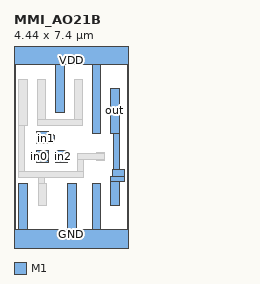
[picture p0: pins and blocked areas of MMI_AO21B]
MACRO MMI_AO21B
	CLASS CORE ;
	FOREIGN MMI_AO21B 0 0 ;
	SIZE 4.44 BY 7.4 ;
	SYMMETRY X Y ;
	SITE CORE1 ;
	PIN out
		DIRECTION output ;
		USE SIGNAL ;
		PORT
			LAYER M1 ;
			RECT 3.76 4.225 4.1 5.985 ;
			LAYER M1 ;
			RECT 3.87 2.815 4.1 4.225 ;
			LAYER M1 ;
			RECT 3.845 2.54 4.295 2.815 ;
			LAYER M1 ;
			RECT 3.76 2.365 4.295 2.54 ;
			LAYER M1 ;
			RECT 3.76 1.435 4.1 2.365 ;
		END
		AntennaDiffArea 1.3248 ;
	END out
	PIN in1
		DIRECTION input ;
		USE SIGNAL ;
		PORT
			LAYER M1 ;
			RECT 0.885 4.19 1.335 4.295 ;
			LAYER M1 ;
			RECT 0.885 4.135 1.52 4.19 ;
			LAYER M1 ;
			RECT 0.885 3.905 1.585 4.135 ;
			LAYER M1 ;
			RECT 0.885 3.85 1.52 3.905 ;
			LAYER M1 ;
			RECT 0.885 3.845 1.335 3.85 ;
		END
		AntennaGateArea 0.4968 ;
	END in1
	PIN GND
		DIRECTION inout ;
		USE GROUND ;
		PORT
			LAYER M1 ;
			RECT 0.18 0.5 0.52 2.275 ;
			LAYER M1 ;
			RECT 2.09 0.5 2.43 2.275 ;
			LAYER M1 ;
			RECT 3.04 0.5 3.38 2.275 ;
			LAYER M1 ;
			RECT 0 -0.5 4.44 0.5 ;
		END
	END GND
	PIN in2
		DIRECTION input ;
		USE SIGNAL ;
		PORT
			LAYER M1 ;
			RECT 1.625 3.5 2.075 3.555 ;
			LAYER M1 ;
			RECT 1.625 3.16 2.2 3.5 ;
			LAYER M1 ;
			RECT 1.625 3.105 2.075 3.16 ;
		END
		AntennaGateArea 0.4968 ;
	END in2
	PIN VDD
		DIRECTION inout ;
		USE POWER ;
		PORT
			LAYER M1 ;
			RECT 0 6.9 4.44 7.9 ;
			LAYER M1 ;
			RECT 1.62 5.03 1.96 6.9 ;
			LAYER M1 ;
			RECT 3.04 4.225 3.38 6.9 ;
		END
	END VDD
	PIN in0
		DIRECTION input ;
		USE SIGNAL ;
		PORT
			LAYER M1 ;
			RECT 0.885 3.5 1.335 3.555 ;
			LAYER M1 ;
			RECT 0.64 3.16 1.335 3.5 ;
			LAYER M1 ;
			RECT 0.885 3.105 1.335 3.16 ;
		END
		AntennaGateArea 0.414 ;
	END in0
	OBS
		LAYER M1 ;
		RECT 0.18 4.55 0.52 6.31 ;
		LAYER M1 ;
		RECT 0.9 4.78 1.24 6.31 ;
		LAYER M1 ;
		RECT 2.34 4.78 2.68 6.31 ;
		LAYER M1 ;
		RECT 0.9 4.55 2.68 4.78 ;
		LAYER M1 ;
		RECT 0.18 2.755 0.41 4.55 ;
		LAYER M1 ;
		RECT 3.195 3.445 3.535 3.5 ;
		LAYER M1 ;
		RECT 2.475 3.215 3.535 3.445 ;
		LAYER M1 ;
		RECT 2.475 2.755 2.705 3.215 ;
		LAYER M1 ;
		RECT 3.195 3.16 3.535 3.215 ;
		LAYER M1 ;
		RECT 0.18 2.525 2.705 2.755 ;
		LAYER M1 ;
		RECT 0.94 2.275 1.17 2.525 ;
		LAYER M1 ;
		RECT 0.94 1.435 1.28 2.275 ;
	END
END MMI_AO21B
